VERSION 5.7 ;
  NOWIREEXTENSIONATPIN ON ;
  DIVIDERCHAR "/" ;
  BUSBITCHARS "[]" ;
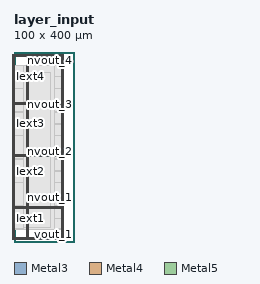
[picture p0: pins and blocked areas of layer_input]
MACRO layer_input
  CLASS BLOCK ;
  FOREIGN layer_input ;
  ORIGIN 0.000 0.000 ;
  SIZE 100.000 BY 400.000 ;
  PIN Iext1
    DIRECTION INPUT ;
    USE SIGNAL ;
    ANTENNAGATEAREA 0.280000 ;
    ANTENNADIFFAREA 1.380000 ;
    PORT
      LAYER Metal3 ;
        RECT 0.000 49.280 0.560 49.840 ;
    END
  END Iext1
  PIN Iext2
    DIRECTION INPUT ;
    USE SIGNAL ;
    ANTENNAGATEAREA 0.280000 ;
    ANTENNADIFFAREA 1.380000 ;
    PORT
      LAYER Metal3 ;
        RECT 0.000 148.960 0.560 149.520 ;
    END
  END Iext2
  PIN Iext3
    DIRECTION INPUT ;
    USE SIGNAL ;
    ANTENNAGATEAREA 0.280000 ;
    ANTENNADIFFAREA 1.380000 ;
    PORT
      LAYER Metal3 ;
        RECT 0.000 248.640 0.560 249.200 ;
    END
  END Iext3
  PIN Iext4
    DIRECTION INPUT ;
    USE SIGNAL ;
    ANTENNAGATEAREA 0.280000 ;
    ANTENNADIFFAREA 1.380000 ;
    PORT
      LAYER Metal3 ;
        RECT 0.000 348.320 0.560 348.880 ;
    END
  END Iext4
  PIN nvout_1
    DIRECTION OUTPUT ;
    USE SIGNAL ;
    ANTENNAGATEAREA 0.560000 ;
    ANTENNADIFFAREA 0.750000 ;
    PORT
      LAYER Metal3 ;
        RECT 99.440 76.160 100.000 76.720 ;
    END
  END nvout_1
  PIN nvout_2
    DIRECTION OUTPUT ;
    USE SIGNAL ;
    ANTENNAGATEAREA 0.560000 ;
    ANTENNADIFFAREA 0.750000 ;
    PORT
      LAYER Metal3 ;
        RECT 99.440 174.720 100.000 175.280 ;
    END
  END nvout_2
  PIN nvout_3
    DIRECTION OUTPUT ;
    USE SIGNAL ;
    ANTENNAGATEAREA 0.560000 ;
    ANTENNADIFFAREA 0.750000 ;
    PORT
      LAYER Metal3 ;
        RECT 99.440 273.280 100.000 273.840 ;
    END
  END nvout_3
  PIN nvout_4
    DIRECTION OUTPUT ;
    USE SIGNAL ;
    ANTENNAGATEAREA 0.560000 ;
    ANTENNADIFFAREA 0.750000 ;
    PORT
      LAYER Metal3 ;
        RECT 99.440 371.840 100.000 372.400 ;
    END
  END nvout_4
  PIN vdd
    DIRECTION INOUT ;
    USE POWER ;
    PORT
      LAYER Metal4 ;
        RECT -0.780 8.180 0.720 391.660 ;
    END
    PORT
      LAYER Metal4 ;
        RECT 98.960 8.180 100.460 391.660 ;
    END
    PORT
      LAYER Metal5 ;
        RECT -0.780 8.180 100.460 9.680 ;
    END
    PORT
      LAYER Metal5 ;
        RECT -0.780 390.160 100.460 391.660 ;
    END
    PORT
      LAYER Metal4 ;
        RECT 26.120 5.180 27.320 394.660 ;
    END
    PORT
      LAYER Metal5 ;
        RECT -3.780 70.080 103.460 71.280 ;
    END
    PORT
      LAYER Metal5 ;
        RECT -3.780 180.080 103.460 181.280 ;
    END
    PORT
      LAYER Metal5 ;
        RECT -3.780 290.080 103.460 291.280 ;
    END
  END vdd
  PIN vout_1
    DIRECTION OUTPUT ;
    USE SIGNAL ;
    ANTENNADIFFAREA 0.750000 ;
    PORT
      LAYER Metal3 ;
        RECT 99.440 26.880 100.000 27.440 ;
    END
  END vout_1
  PIN vout_2
    DIRECTION OUTPUT ;
    USE SIGNAL ;
    ANTENNADIFFAREA 0.750000 ;
    PORT
      LAYER Metal3 ;
        RECT 99.440 125.440 100.000 126.000 ;
    END
  END vout_2
  PIN vout_3
    DIRECTION OUTPUT ;
    USE SIGNAL ;
    ANTENNADIFFAREA 0.750000 ;
    PORT
      LAYER Metal3 ;
        RECT 99.440 224.000 100.000 224.560 ;
    END
  END vout_3
  PIN vout_4
    DIRECTION OUTPUT ;
    USE SIGNAL ;
    ANTENNADIFFAREA 0.750000 ;
    PORT
      LAYER Metal3 ;
        RECT 99.440 322.560 100.000 323.120 ;
    END
  END vout_4
  PIN vss
    DIRECTION INOUT ;
    USE GROUND ;
    PORT
      LAYER Metal4 ;
        RECT -3.780 5.180 -2.280 394.660 ;
    END
    PORT
      LAYER Metal4 ;
        RECT 101.960 5.180 103.460 394.660 ;
    END
    PORT
      LAYER Metal5 ;
        RECT -3.780 5.180 103.460 6.680 ;
    END
    PORT
      LAYER Metal5 ;
        RECT -3.780 393.160 103.460 394.660 ;
    END
    PORT
      LAYER Metal4 ;
        RECT 29.320 5.180 30.520 394.660 ;
    END
    PORT
      LAYER Metal5 ;
        RECT -3.780 73.280 103.460 74.480 ;
    END
    PORT
      LAYER Metal5 ;
        RECT -3.780 183.280 103.460 184.480 ;
    END
    PORT
      LAYER Metal5 ;
        RECT -3.780 293.280 103.460 294.480 ;
    END
  END vss
  OBS
      LAYER Nwell ;
        RECT 22.000 33.300 75.860 353.890 ;
      LAYER Metal1 ;
        RECT 22.190 33.510 75.630 353.680 ;
      LAYER Metal2 ;
        RECT 20.650 30.250 76.170 357.640 ;
      LAYER Metal3 ;
        RECT 0.560 371.540 99.140 372.260 ;
        RECT 0.560 349.180 99.540 371.540 ;
        RECT 0.860 348.020 99.540 349.180 ;
        RECT 0.560 323.420 99.540 348.020 ;
        RECT 0.560 322.260 99.140 323.420 ;
        RECT 0.560 274.140 99.540 322.260 ;
        RECT 0.560 272.980 99.140 274.140 ;
        RECT 0.560 249.500 99.540 272.980 ;
        RECT 0.860 248.340 99.540 249.500 ;
        RECT 0.560 224.860 99.540 248.340 ;
        RECT 0.560 223.700 99.140 224.860 ;
        RECT 0.560 175.580 99.540 223.700 ;
        RECT 0.560 174.420 99.140 175.580 ;
        RECT 0.560 149.820 99.540 174.420 ;
        RECT 0.860 148.660 99.540 149.820 ;
        RECT 0.560 126.300 99.540 148.660 ;
        RECT 0.560 125.140 99.140 126.300 ;
        RECT 0.560 77.020 99.540 125.140 ;
        RECT 0.560 75.860 99.140 77.020 ;
        RECT 0.560 50.140 99.540 75.860 ;
        RECT 0.860 48.980 99.540 50.140 ;
        RECT 0.560 27.740 99.540 48.980 ;
        RECT 0.560 27.020 99.140 27.740 ;
      LAYER Metal4 ;
        RECT 20.650 26.970 25.820 372.310 ;
        RECT 27.620 26.970 29.020 372.310 ;
        RECT 30.820 26.970 84.420 372.310 ;
      LAYER Metal5 ;
        RECT 20.000 295.080 77.860 357.890 ;
        RECT 20.000 291.880 77.860 292.680 ;
        RECT 20.000 185.080 77.860 289.480 ;
        RECT 20.000 181.880 77.860 182.680 ;
        RECT 20.000 75.080 77.860 179.480 ;
        RECT 20.000 71.880 77.860 72.680 ;
        RECT 20.000 30.000 77.860 69.480 ;
  END
END layer_input
END LIBRARY

